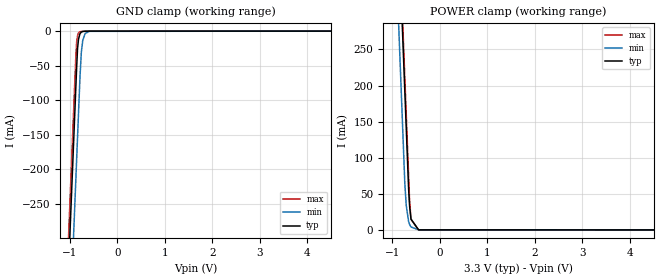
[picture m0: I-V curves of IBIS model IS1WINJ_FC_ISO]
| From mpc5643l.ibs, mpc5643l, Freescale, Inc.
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| *** New cell (Generated with 5.14beta1 (Sep 20 2010 13:23:23))
[Model]   IS1WINJ_FC_ISO
Model_type Input
Polarity   Non-Inverting
Enable   Active-Low
| CAP_THRESHOLD on pad pad is "CMOS" :
| Rising=10.0% of VDDE1   Falling=90.0% of VDDE1
| C_comp min and max val. don't necessarily correlate with the min and max pvt
| but are the smallest and greatest pad capacitance found.
| var   typ   min   max
C_comp   1.91911pF  1.69535pF  2.25191pF
Vinl = 800.0mV | Dummy value overriden by next lines
Vinh = 2.0V | Dummy value overriden by next lines
[Model Spec]
| TIME_THRESHOLD on pin ipp_ind is "CORE" :
| Rising=40.0% of VDD   Falling=60.0% of VDD
Vinl 1.33450V 1.25450V 1.40350V
Vinh 1.94950V 1.74350V 2.18850V
| variable   typ   min   max
[Temperature Range] 25.0 150.0 -40.0
| variable   typ   min   max
[Voltage Range] 3.3V 3.0V 3.6V
| variable   typ   min   max
[POWER Clamp Reference] 3.3V 3.0V 3.6V
| variable   typ   min   max
[GND Clamp Reference] 0V 0V 0V
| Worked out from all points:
|   GND clamp passes 1 mA (typ) near -0.75 V on its own axis
|   POWER clamp passes 1 mA (typ) near -0.51 V on its own axis
[POWER Clamp]
-3.3V     4.545A     4.416A     4.564A
-1.21V    991.9mA    862.7mA    1.011A
-1.2V     974.9mA    845.7mA    993.8mA
-1.14V    872.9mA    743.7mA    891.8mA
-1.07V    753.9mA    624.7mA    772.8mA
-740mV    192.9mA    64.92mA    211.8mA
-710mV    141.9mA    33.94mA    160.8mA
-660mV    57.08mA    11.75mA    75.77mA
-640mV    33.66mA    7.739mA    41.99mA
-610mV    14.99mA    4.167mA    15mA
-450mV    183.9uA    169.1uA    57.2uA
6.6V      0A         0A         0A
[GND Clamp]
-3.3V     -4.202A    -4.335A    -4.157A
-1.08V    -427.9mA   -561.1mA   -382.8mA
-880mV    -87.86mA   -221.1mA   -42.79mA
-860mV    -53.86mA   -187.1mA   -16.15mA
-840mV    -25.12mA   -153.1mA   -6.281mA
-820mV    -11.75mA   -119.1mA   -2.603mA
-790mV    -3.888mA   -68.11mA   -885.3uA
-760mV    -1.399mA   -30.03mA   -452.5uA
-730mV    -584.5uA   -13.28mA   -312.5uA
-680mV    -208uA     -3.448mA   -208.3uA
-590mV    -62.42uA   -337.3uA   -94.03uA
6.6V      57.08nA    1.538uA    579.2pA
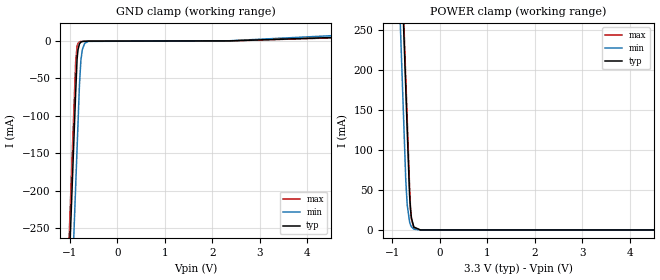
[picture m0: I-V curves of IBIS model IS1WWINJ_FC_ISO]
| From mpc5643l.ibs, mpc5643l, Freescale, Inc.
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| *** New cell (Generated with 5.14beta1 (Sep 20 2010 13:23:23))
[Model]   IS1WWINJ_FC_ISO
Model_type Input
Polarity   Non-Inverting
Enable   Active-Low
| CAP_THRESHOLD on pad pad is "CMOS" :
| Rising=10.0% of VDDE1   Falling=90.0% of VDDE1
| C_comp min and max val. don't necessarily correlate with the min and max pvt
| but are the smallest and greatest pad capacitance found.
| var   typ   min   max
C_comp   2.72699pF  2.41350pF  3.20536pF
Vinl = 800.0mV | Dummy value overriden by next lines
Vinh = 2.0V | Dummy value overriden by next lines
[Model Spec]
| TIME_THRESHOLD on pin ipp_ind is "CORE" :
| Rising=40.0% of VDD   Falling=60.0% of VDD
Vinl 1.33450V 1.25450V 1.40350V
Vinh 1.94950V 1.74350V 2.18850V
| variable   typ   min   max
[Temperature Range] 25.0 150.0 -40.0
| variable   typ   min   max
[Voltage Range] 3.3V 3.0V 3.6V
| variable   typ   min   max
[POWER Clamp Reference] 3.3V 3.0V 3.6V
| variable   typ   min   max
[GND Clamp Reference] 0V 0V 0V
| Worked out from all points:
|   GND clamp passes 1 mA (typ) near -0.76 V on its own axis
|   POWER clamp passes 1 mA (typ) near -0.51 V on its own axis
[POWER Clamp]
-3.3V     4.558A     4.44A      4.573A
-1.21V    1.009A     893.4mA    1.023A
-1.14V    889.9mA    774.7mA    904.4mA
-1.07V    771mA      655.9mA    785.5mA
-720mV    176.6mA    62.81mA    190.9mA
-690mV    125.6mA    31.8mA     140mA
-640mV    44.03mA    10.22mA    55.06mA
-620mV    25.54mA    6.433mA    27.54mA
-600mV    14.73mA    3.992mA    13.69mA
-550mV    3.644mA    1.03mA     2.347mA
-410mV    5.18uA     0A         0A
6.6V      0A         0A         0A
[GND Clamp]
-3.3V     -4.183A    -4.308A    -4.142A
-1.08V    -409.1mA   -534.4mA   -368.1mA
-880mV    -69.11mA   -194.4mA   -28.13mA
-850mV    -24.23mA   -143.4mA   -6.805mA
-830mV    -11.4mA    -109.4mA   -2.875mA
-800mV    -3.852mA   -58.38mA   -1.042mA
-770mV    -1.458mA   -25.81mA   -580.1uA
-740mV    -668.9uA   -11.47mA   -428.9uA
-690mV    -291.3uA   -3.045mA   -309.2uA
-610mV    -125.6uA   -429.9uA   -173.6uA
2.36V     212.7uA    352uA      145uA
6.6V      8.987mA    13.78mA    8.099mA
